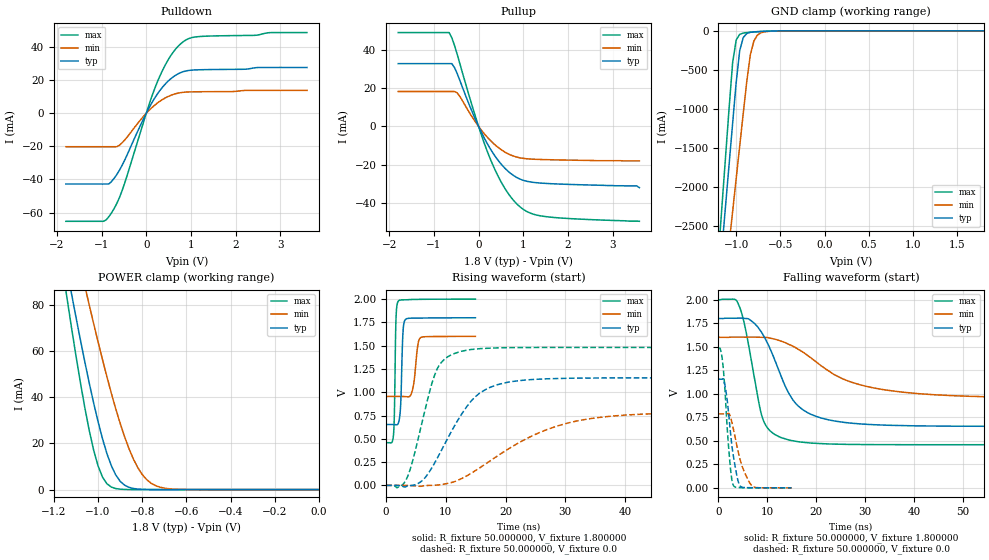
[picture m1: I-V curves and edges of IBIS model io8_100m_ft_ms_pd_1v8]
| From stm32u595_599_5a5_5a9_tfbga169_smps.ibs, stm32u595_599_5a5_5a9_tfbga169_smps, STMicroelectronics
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|   Model io8_100m_ft_ms_pd_1v8
[Model]  io8_100m_ft_ms_pd_1v8
Model_type I/O
Polarity   Non-Inverting
Enable   Active-Low
Vinl =   0.540000V
Vinh =   1.260000V
Vmeas =  0.900000V
Cref =   50.000000pF
Rref =   100.000000M
Vref =   0.0V
C_comp   3.148300pF   3.147400pF   3.196500pF
[Temperature Range]   25.000000   0.140000k   -40.000000
[Pullup Reference]   1.800000V   1.600000V   2.000000V
[Pulldown Reference]   0.0V   0.0V   0.0V
[POWER Clamp Reference]   1.800000V   1.600000V   2.000000V
[GND Clamp Reference]   0.0V   0.0V   0.0V
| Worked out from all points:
|   slope of the pulldown table from 0 to 0.27 V, typ, clamps not added: 21.7 ohm
|   slope of the pullup table from 0 to 0.27 V, typ, clamps not added: 22.6 ohm
|   GND clamp passes 1 mA (typ) near -0.51 V on its own axis
|   POWER clamp passes 1 mA (typ) near -0.86 V on its own axis
|   rising waveform, R_fixture 50.000000, V_fixture 1.800000: 20-80 % time 319ps typ, 632ps min, 231ps max; typ from 0.654 V to 1.8 V
|   rising waveform, R_fixture 50.000000, V_fixture 0.0: 20-80 % time 6.48ns typ, 13.4ns min, 3.56ns max; typ from 0 V to 1.15 V
|   falling waveform, R_fixture 50.000000, V_fixture 1.800000: 20-80 % time 6.37ns typ, 13.5ns min, 3.36ns max; typ from 1.8 V to 0.654 V
|   falling waveform, R_fixture 50.000000, V_fixture 0.0: 20-80 % time 1.6ns typ, 2.38ns min, 1.18ns max; typ from 1.15 V to 0 V
[Pulldown]
|Voltage   I(typ)   I(min)   I(max)
-1.8V     -42.74mA   -20.21mA   -65.25mA
-960mV    -42.74mA   -20.21mA   -65.25mA
-780mV    -41.3mA    -20.21mA   -60.25mA
-660mV    -37mA      -20.2mA    -54.5mA
-540mV    -31.39mA   -17.82mA   -46.65mA
0V        0A         100fA      0A
240mV     11.28mA    6.002mA    18.38mA
480mV     19.17mA    10.02mA    31.83mA
780mV     24.67mA    12.5mA     42.21mA
960mV     25.9mA     12.9mA     45.21mA
1.14V     26.24mA    12.99mA    46.23mA
3.6V      27.67mA    13.81mA    48.75mA
[Pullup]
|Voltage   I(typ)   I(min)   I(max)
-1.8V     32.87mA    18.3mA     49.13mA
-660mV    32.87mA    18.3mA     49.13mA
-600mV    32.87mA    18.3mA     46.41mA
-480mV    27.73mA    17.56mA    37.8mA
-60mV     3.108mA    1.975mA    4.436mA
240mV     -10.82mA   -6.752mA   -15.73mA
420mV     -17.18mA   -10.64mA   -25.23mA
600mV     -22.1mA    -13.54mA   -32.82mA
960mV     -27.82mA   -16.55mA   -42.66mA
1.2V      -29.16mA   -17.09mA   -45.68mA
1.56V     -29.85mA   -17.37mA   -47.3mA
3.6V      -32mA      -18mA      -49.6mA
[GND_clamp]
|Voltage   I(typ)   I(min)   I(max)
-1.8V     -9.707A    -9.942A    -9.774A
-1.2V     -3.309A    -4.006A    -2.865A
-1.16V    -2.777A    -3.584A    -2.239A
-1.12V    -2.246A    -3.162A    -1.614A
-1.04V    -1.186A    -2.319A    -408.7mA
-1V       -663.9mA   -1.898A    -117.8mA
-960mV    -254mA     -1.478A    -45.15mA
-920mV    -86.04mA   -1.06A     -28.6mA
-840mV    -19.13mA   -308.9mA   -18.75mA
-800mV    -13.4mA    -130.8mA   -15.33mA
-720mV    -7.959mA   -25.38mA   -9.395mA
1.8V      45.71uA    33.33uA    56.11uA
[POWER_clamp]
|Voltage   I(typ)   I(min)   I(max)
-1.8V     470.8mA    433.7mA    554.6mA
-1.14V    95.25mA    122.7mA    82.82mA
-1.12V    84.97mA    114mA      70.27mA
-1.06V    55.51mA    88.42mA    35.67mA
-1.04V    46.34mA    80.15mA    25.76mA
-1V       29.51mA    64.13mA    10.3mA
-940mV    10.39mA    41.86mA    1.109mA
-900mV    3.624mA    28.77mA    182.8uA
-840mV    490.7uA    13.24mA    11.35uA
-800mV    116.8uA    6.532mA    1.77uA
-740mV    13.2uA     1.723mA    109.3nA
0V        0A         18.72nA    0A
[Ramp]
| variable   typ   min   max
dV/dt_r  0.69264/6.46919n   0.47164/13.34441n   0.88830/3.56051n
dV/dt_f  0.68753/6.36026n   0.38683/13.47507n   0.92452/3.34799n
R_load = 50.000000
[Rising Waveform]
R_fixture= 50.000000
V_fixture= 1.800000
V_fixture_min= 1.600000
V_fixture_max= 2.000000
|time   V(typ)   V(min)   V(max)
0s        653.5mV    954.4mV    458.5mV
1.231ns   653.4mV    954.4mV    543.8mV
1.652ns   650.6mV    954.4mV    1.793V
2.012ns   663.5mV    954.5mV    1.976V
2.432ns   866.1mV    954.4mV    1.99V
2.853ns   1.674V     954.2mV    1.992V
3.213ns   1.78V      953.2mV    1.992V
4.414ns   1.795V     1.025V     1.995V
5.676ns   1.796V     1.581V     1.997V
14.95ns   1.799V     1.599V     1.999V
[Rising Waveform]
R_fixture= 50.000000
V_fixture= 0.0
V_fixture_min= 0.0
V_fixture_max= 0.0
|time   V(typ)   V(min)   V(max)
0s        3.631uV    3.094uV    2.535uV
3.203ns   -17.22mV   118.3uV    44.34mV
6.006ns   49.36mV    -7.78mV    673.8mV
8.408ns   273.4mV    2.738mV    1.231V
12.61ns   761.6mV    72.13mV    1.44V
15.62ns   988mV      185.6mV    1.467V
18.62ns   1.08V      314.6mV    1.476V
26.83ns   1.144V     596.4mV    1.48V
35.44ns   1.153V     727.3mV    1.48V
99.7ns    1.154V     786.2mV    1.48V
[Falling Waveform]
R_fixture= 50.000000
V_fixture= 1.800000
V_fixture_min= 1.600000
V_fixture_max= 2.000000
|time   V(typ)   V(min)   V(max)
0s        1.799V     1.599V     1.999V
3.804ns   1.803V     1.602V     1.981V
5.405ns   1.8V       1.601V     1.717V
8.408ns   1.683V     1.6V       866.4mV
9.209ns   1.618V     1.599V     713.7mV
14.41ns   1.003V     1.524V     508.5mV
17.22ns   832.1mV    1.445V     484.8mV
21.02ns   742.1mV    1.297V     470.3mV
34.63ns   665.4mV    1.037V     459.2mV
99.7ns    653.5mV    954.4mV    458.5mV
[Falling Waveform]
R_fixture= 50.000000
V_fixture= 0.0
V_fixture_min= 0.0
V_fixture_max= 0.0
|time   V(typ)   V(min)   V(max)
0s        1.154V     786.2mV    1.48V
750.8ps   1.155V     786.2mV    1.377V
1.321ns   1.091V     786.1mV    1.043V
1.802ns   922.7mV    787.6mV    621.8mV
2.312ns   662.1mV    774.6mV    283.9mV
2.703ns   467.2mV    705.1mV    97.18mV
3.093ns   323.6mV    614.9mV    22.17mV
4.444ns   18.73mV    296.3mV    2.615mV
6.787ns   1.414mV    24.79mV    615.3uV
14.95ns   3.631uV    3.094uV    2.535uV
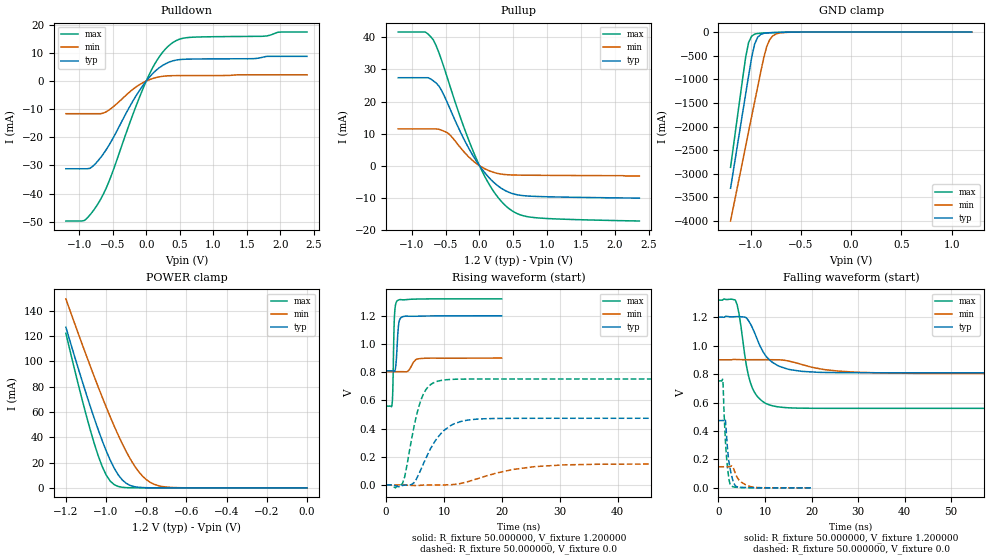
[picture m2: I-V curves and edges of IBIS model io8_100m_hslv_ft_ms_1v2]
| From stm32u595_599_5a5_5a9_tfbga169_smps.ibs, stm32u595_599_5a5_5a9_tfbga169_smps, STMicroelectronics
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|   Model io8_100m_hslv_ft_ms_1v2
[Model]  io8_100m_hslv_ft_ms_1v2
Model_type I/O
Polarity   Non-Inverting
Enable   Active-Low
Vinl =   0.360000V
Vinh =   0.840000V
Vmeas =  0.600000V
Cref =   50.000000pF
Rref =   100.000000M
Vref =   0.0V
C_comp   3.030100pF   2.960800pF   3.078300pF
[Temperature Range]   25.000000   0.140000k   -40.000000
[Pullup Reference]   1.200000V   0.900000V   1.320000V
[Pulldown Reference]   0.0V   0.0V   0.0V
[POWER Clamp Reference]   1.200000V   0.900000V   1.320000V
[GND Clamp Reference]   0.0V   0.0V   0.0V
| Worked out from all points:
|   slope of the pulldown table from 0 to 0.18 V, typ, clamps not added: 40.7 ohm
|   slope of the pullup table from 0 to 0.18 V, typ, clamps not added: 39.5 ohm
|   GND clamp passes 1 mA (typ) near -0.51 V on its own axis
|   POWER clamp passes 1 mA (typ) near -0.86 V on its own axis
|   rising waveform, R_fixture 50.000000, V_fixture 1.200000: 20-80 % time 356ps typ, 869ps min, 231ps max; typ from 0.809 V to 1.2 V
|   rising waveform, R_fixture 50.000000, V_fixture 0.0: 20-80 % time 3.94ns typ, 8.94ns min, 2.36ns max; typ from 0 V to 0.473 V
|   falling waveform, R_fixture 50.000000, V_fixture 1.200000: 20-80 % time 4.07ns typ, 8.67ns min, 2.49ns max; typ from 1.2 V to 0.809 V
|   falling waveform, R_fixture 50.000000, V_fixture 0.0: 20-80 % time 1.04ns typ, 1.97ns min, 798ps max; typ from 0.473 V to 0 V
[Pulldown]
|Voltage   I(typ)   I(min)   I(max)
-1.2V     -31.16mA   -11.61mA   -49.71mA
-920mV    -31.16mA   -11.61mA   -49.48mA
-840mV    -31mA      -11.61mA   -47.54mA
-720mV    -28.32mA   -11.61mA   -43.58mA
-560mV    -22.95mA   -10.37mA   -35.89mA
-200mV    -7.146mA   -2.964mA   -11.89mA
0V        0A         -900fA     0A
160mV     4.047mA    1.298mA    7.361mA
360mV     6.87mA     1.87mA     13mA
640mV     7.764mA    1.923mA    15.46mA
1.76V     8.564mA    2.187mA    15.9mA
2.4V      8.742mA    2.187mA    17.38mA
[Pullup]
|Voltage   I(typ)   I(min)   I(max)
-1.2V     27.43mA    11.47mA    41.67mA
-800mV    27.43mA    11.47mA    41.67mA
-680mV    26.42mA    11.47mA    39.17mA
-600mV    24.87mA    11.36mA    35.26mA
-440mV    17.97mA    9.699mA    25.09mA
-240mV    8.719mA    4.584mA    12.56mA
-40mV     1.247mA    576.2uA    1.879mA
200mV     -4.978mA   -2.01mA    -7.739mA
440mV     -8.335mA   -2.843mA   -13.44mA
600mV     -9.206mA   -2.931mA   -15.29mA
840mV     -9.571mA   -2.98mA    -16.23mA
2.36V     -10.1mA    -3.2mA     -17.23mA
[GND_clamp]
|Voltage   I(typ)   I(min)   I(max)
-1.2V     -3.305A    -3.998A    -2.862A
-1.05V    -1.316A    -2.418A    -539.3mA
-1.02V    -921mA     -2.103A    -218.8mA
-990mV    -539.5mA   -1.788A    -87.43mA
-960mV    -252.1mA   -1.474A    -44.36mA
-930mV    -110.5mA   -1.16A     -30.32mA
-870mV    -28.03mA   -549.1mA   -21.09mA
-840mV    -18.43mA   -305.6mA   -18.27mA
-810mV    -13.9mA    -159.7mA   -15.73mA
-780mV    -11.23mA   -82.35mA   -13.37mA
-600mV    -2.976mA   -4.272mA   -3.058mA
1.2V      0A         14.73nA    0A
[POWER_clamp]
|Voltage   I(typ)   I(min)   I(max)
-1.2V     127mA      149.4mA    122.2mA
-1.12V    84.97mA    114mA      70.27mA
-1.06V    55.51mA    88.42mA    35.67mA
-1.02V    37.63mA    72.04mA    17.17mA
-1V       29.51mA    64.13mA    10.3mA
-960mV    15.69mA    48.99mA    2.571mA
-900mV    3.624mA    28.77mA    182.8uA
-840mV    490.7uA    13.24mA    11.35uA
-800mV    116.8uA    6.532mA    1.77uA
-740mV    13.2uA     1.723mA    109.1nA
-620mV    167.3nA    79.35uA    0A
0V        0A         17.84nA    0A
[Ramp]
| variable   typ   min   max
dV/dt_r  0.28375/3.90597n   88.91987m/8.93167n  0.45093/2.35229n
dV/dt_f  0.23463/4.02925n   57.91200m/8.66486n  0.45666/2.47766n
R_load = 50.000000
[Rising Waveform]
R_fixture= 50.000000
V_fixture= 1.200000
V_fixture_min= 0.900000
V_fixture_max= 1.320000
|time   V(typ)   V(min)   V(max)
0s        809mV      803.5mV    558.9mV
1.041ns   809.4mV    803.5mV    578.2mV
1.161ns   809.1mV    803.5mV    693.9mV
1.321ns   806.9mV    803.6mV    1.049V
1.441ns   805.2mV    803.6mV    1.204V
1.922ns   1.007V     803.6mV    1.307V
2.242ns   1.16V      803.7mV    1.314V
2.923ns   1.194V     803.4mV    1.313V
5.726ns   1.197V     895.5mV    1.319V
19.94ns   1.2V       900mV      1.32V
[Rising Waveform]
R_fixture= 50.000000
V_fixture= 0.0
V_fixture_min= 0.0
V_fixture_max= 0.0
|time   V(typ)   V(min)   V(max)
0s        2.231nV    213nV      1.42nV
2.803ns   -4.399mV   53.9uV     8.088mV
3.203ns   -1.385mV   38.83uV    57.98mV
4.805ns   15.36mV    -4.229mV   412.6mV
6.406ns   147.7mV    -1.253mV   642.3mV
8.008ns   280.7mV    -164.1uV   720.8mV
10.41ns   399.2mV    308.8uV    746.4mV
15.22ns   465.1mV    36.85mV    751.2mV
30.83ns   472.8mV    142.1mV    751.5mV
199.4ns   472.9mV    148.2mV    751.6mV
[Falling Waveform]
R_fixture= 50.000000
V_fixture= 1.200000
V_fixture_min= 0.900000
V_fixture_max= 1.320000
|time   V(typ)   V(min)   V(max)
0s        1.2V       900mV      1.32V
3.604ns   1.203V     902.5mV    1.321V
4.004ns   1.204V     901.9mV    1.288V
6.006ns   1.196V     900.8mV    858.6mV
7.608ns   1.102V     900.9mV    679.2mV
10.01ns   934.9mV    900.9mV    596.2mV
13.21ns   852.7mV    900.1mV    567.7mV
22.82ns   811.3mV    831.1mV    559.1mV
35.24ns   809mV      807.5mV    558.9mV
199.4ns   809mV      803.5mV    558.9mV
[Falling Waveform]
R_fixture= 50.000000
V_fixture= 0.0
V_fixture_min= 0.0
V_fixture_max= 0.0
|time   V(typ)   V(min)   V(max)
0s        472.9mV    148.2mV    751.6mV
920.9ps   473.2mV    148.3mV    760.5mV
1.201ns   474.7mV    148.3mV    524.5mV
1.441ns   482.1mV    148.4mV    360.6mV
1.682ns   391.2mV    148.4mV    236.8mV
2.202ns   194.6mV    148.2mV    72.35mV
2.683ns   104.6mV    152.2mV    16.41mV
3.764ns   10.77mV    90.01mV    3.994mV
6.767ns   1.663mV    9.962mV    590uV
19.94ns   2.231nV    213nV      1.42nV
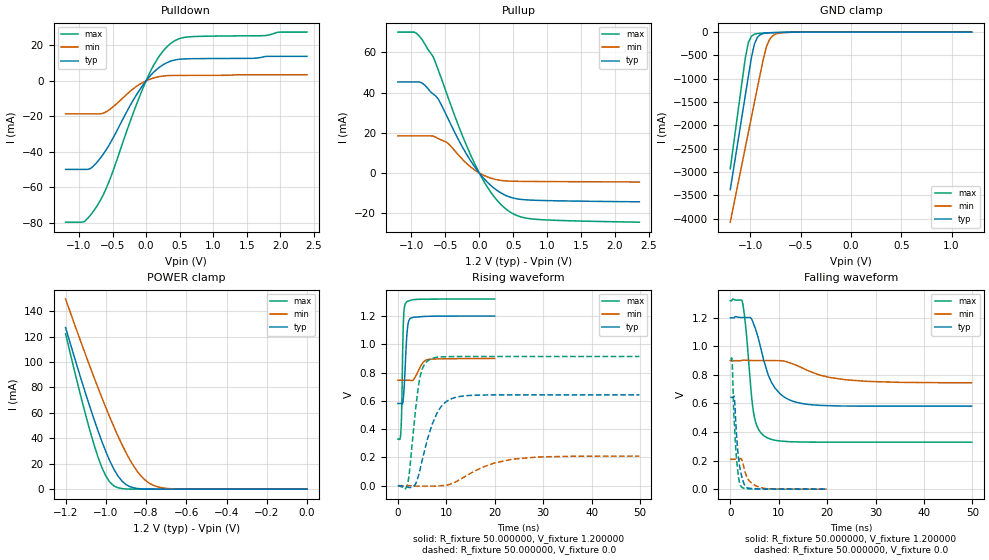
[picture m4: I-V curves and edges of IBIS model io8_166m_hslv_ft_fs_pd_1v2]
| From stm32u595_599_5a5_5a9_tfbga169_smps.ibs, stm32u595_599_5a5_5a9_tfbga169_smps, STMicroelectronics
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|   Model io8_166m_hslv_ft_fs_pd_1v2
[Model]  io8_166m_hslv_ft_fs_pd_1v2
Model_type I/O
Polarity   Non-Inverting
Enable   Active-Low
Vinl =   0.360000V
Vinh =   0.840000V
Vmeas =  0.600000V
Cref =   50.000000pF
Rref =   100.000000M
Vref =   0.0V
C_comp   3.151700pF   3.087200pF   3.197900pF
[Temperature Range]   25.000000   0.140000k   -40.000000
[Pullup Reference]   1.200000V   0.900000V   1.320000V
[Pulldown Reference]   0.0V   0.0V   0.0V
[POWER Clamp Reference]   1.200000V   0.900000V   1.320000V
[GND Clamp Reference]   0.0V   0.0V   0.0V
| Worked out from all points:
|   slope of the pulldown table from 0 to 0.18 V, typ, clamps not added: 25.4 ohm
|   slope of the pullup table from 0 to 0.18 V, typ, clamps not added: 27.8 ohm
|   GND clamp passes 1 mA (typ) near -0.51 V on its own axis
|   POWER clamp passes 1 mA (typ) near -0.86 V on its own axis
|   rising waveform, R_fixture 50.000000, V_fixture 1.200000: 20-80 % time 570ps typ, 1.42ns min, 326ps max; typ from 0.581 V to 1.2 V
|   rising waveform, R_fixture 50.000000, V_fixture 0.0: 20-80 % time 3.42ns typ, 8.15ns min, 1.74ns max; typ from 0 V to 0.642 V
|   falling waveform, R_fixture 50.000000, V_fixture 1.200000: 20-80 % time 3.69ns typ, 8.16ns min, 1.62ns max; typ from 1.2 V to 0.581 V
|   falling waveform, R_fixture 50.000000, V_fixture 0.0: 20-80 % time 1.04ns typ, 1.73ns min, 831ps max; typ from 0.642 V to 0 V
[Pulldown]
|Voltage   I(typ)   I(min)   I(max)
-1.2V     -49.86mA   -18.57mA   -79.56mA
-920mV    -49.86mA   -18.57mA   -79.19mA
-840mV    -49.6mA    -18.57mA   -76.08mA
-720mV    -45.32mA   -18.57mA   -69.74mA
-560mV    -36.71mA   -16.58mA   -57.44mA
-200mV    -11.43mA   -4.74mA    -19.03mA
0V        -10fA      -600fA     0A
160mV     6.477mA    2.075mA    11.78mA
360mV     10.99mA    2.99mA     20.81mA
480mV     12.07mA    3.054mA    23.53mA
640mV     12.43mA    3.075mA    24.76mA
2.4V      13.79mA    3.434mA    27.44mA
[Pullup]
|Voltage   I(typ)   I(min)   I(max)
-1.2V     45.31mA    18.46mA    70.12mA
-920mV    45.31mA    18.46mA    69.36mA
-840mV    44.69mA    18.46mA    66.16mA
-680mV    39.3mA     18.37mA    57.86mA
-600mV    36.53mA    16.99mA    50.82mA
-480mV    28.42mA    15.27mA    39.5mA
-280mV    14.84mA    7.943mA    21.22mA
-80mV     3.667mA    1.75mA     5.47mA
160mV     -5.889mA   -2.43mA    -9.115mA
400mV     -11.31mA   -3.958mA   -18.11mA
800mV     -13.54mA   -4.214mA   -22.92mA
2.36V     -14.3mA    -4.5mA     -24.47mA
[GND_clamp]
|Voltage   I(typ)   I(min)   I(max)
-1.2V     -3.379A    -4.076A    -2.932A
-1.05V    -1.35A     -2.47A     -550.7mA
-1.02V    -947.8mA   -2.15A     -221.5mA
-990mV    -552.4mA   -1.829A    -88.45mA
-960mV    -255.3mA   -1.51A     -44.89mA
-930mV    -111.8mA   -1.191A    -30.7mA
-870mV    -28.37mA   -564.6mA   -21.36mA
-840mV    -18.66mA   -309.5mA   -18.51mA
-810mV    -14.08mA   -161.6mA   -15.94mA
-780mV    -11.38mA   -83.33mA   -13.55mA
-600mV    -3.02mA    -4.329mA   -3.104mA
1.2V      30.28uA    18.17uA    37.27uA
[POWER_clamp]
|Voltage   I(typ)   I(min)   I(max)
-1.2V     127mA      149.4mA    122.2mA
-1.12V    84.97mA    114mA      70.27mA
-1.06V    55.51mA    88.42mA    35.67mA
-1.02V    37.63mA    72.04mA    17.17mA
-1V       29.51mA    64.13mA    10.3mA
-960mV    15.69mA    48.99mA    2.571mA
-900mV    3.624mA    28.77mA    182.8uA
-840mV    490.7uA    13.24mA    11.35uA
-800mV    116.8uA    6.532mA    1.77uA
-740mV    13.2uA     1.723mA    109.1nA
-620mV    167.4nA    79.36uA    0A
0V        0A         17.87nA    0A
[Ramp]
| variable   typ   min   max
dV/dt_r  0.38524/3.41600n   0.12534/8.13853n   0.54787/1.73624n
dV/dt_f  0.37096/3.68416n   92.53200m/8.16964n  0.59419/1.62055n
R_load = 50.000000
[Rising Waveform]
R_fixture= 50.000000
V_fixture= 1.200000
V_fixture_min= 0.900000
V_fixture_max= 1.320000
|time   V(typ)   V(min)   V(max)
0s        581.3mV    745.1mV    329.3mV
640.6ps   581.2mV    745.1mV    401.8mV
800.8ps   578.7mV    745.1mV    575.7mV
1.121ns   619mV      745.1mV    1.149V
1.321ns   717.3mV    745.1mV    1.256V
1.682ns   973.1mV    745.2mV    1.295V
2.122ns   1.149V     745.3mV    1.305V
2.843ns   1.187V     743.5mV    1.313V
6.206ns   1.198V     892.5mV    1.319V
19.94ns   1.2V       899.5mV    1.319V
[Rising Waveform]
R_fixture= 50.000000
V_fixture= 0.0
V_fixture_min= 0.0
V_fixture_max= 0.0
|time   V(typ)   V(min)   V(max)
0s        -5.805uV   233.2nV    -33.15uV
2.002ns   -9.168mV   -3.342uV   12mV
3.504ns   5.656mV    -2.806mV   492.1mV
4.404ns   92.41mV    -2.955mV   739.4mV
5.205ns   207.6mV    -2.962mV   839.5mV
6.406ns   362.4mV    -3.286mV   889.4mV
8.909ns   558mV      -278.1uV   910.5mV
12.51ns   629.1mV    37.93mV    913mV
23.52ns   642.1mV    186.8mV    913.3mV
49.85ns   642.2mV    209.1mV    913.3mV
[Falling Waveform]
R_fixture= 50.000000
V_fixture= 1.200000
V_fixture_min= 0.900000
V_fixture_max= 1.320000
|time   V(typ)   V(min)   V(max)
0s        1.2V       899.5mV    1.319V
2.503ns   1.202V     902.6mV    1.313V
3.203ns   1.202V     902.6mV    1.133V
4.805ns   1.159V     900.4mV    537.9mV
5.706ns   1.067V     900.2mV    427.7mV
7.307ns   857.9mV    900.1mV    366mV
10.31ns   666.8mV    899.6mV    337.2mV
15.02ns   598.4mV    846.2mV    329.9mV
23.92ns   582.2mV    765.5mV    329.3mV
49.85ns   581.3mV    745.1mV    329.3mV
[Falling Waveform]
R_fixture= 50.000000
V_fixture= 0.0
V_fixture_min= 0.0
V_fixture_max= 0.0
|time   V(typ)   V(min)   V(max)
0s        642.2mV    209.1mV    913.3mV
400.4ps   642.2mV    209.1mV    886.3mV
680.7ps   647.3mV    209.2mV    573mV
840.8ps   643.4mV    209.2mV    462mV
1.441ns   314mV      209.1mV    161.6mV
1.842ns   182.5mV    210.2mV    57.52mV
2.202ns   113.2mV    214.1mV    19.84mV
3.243ns   15mV       101.4mV    3.353mV
5.806ns   1.787mV    16.01mV    457.8uV
19.94ns   -5.805uV   233.2nV    -33.15uV
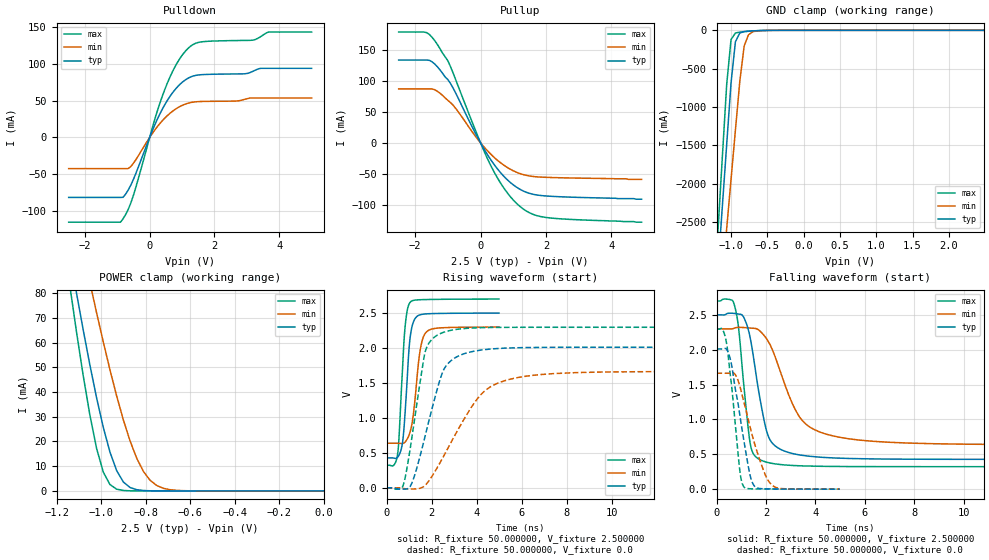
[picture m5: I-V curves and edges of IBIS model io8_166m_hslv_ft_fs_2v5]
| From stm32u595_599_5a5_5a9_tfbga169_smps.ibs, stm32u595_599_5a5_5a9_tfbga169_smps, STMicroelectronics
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|   Model io8_166m_hslv_ft_fs_2v5
[Model]  io8_166m_hslv_ft_fs_2v5
Model_type I/O
Polarity   Non-Inverting
Enable   Active-Low
Vinl =   0.750000V
Vinh =   1.750000V
Vmeas =  1.250000V
Cref =   50.000000pF
Rref =   100.000000M
Vref =   0.0V
C_comp   3.458600pF   3.458000pF   3.495600pF
[Temperature Range]   25.000000   0.140000k   -40.000000
[Pullup Reference]   2.500000V   2.300000V   2.700000V
[Pulldown Reference]   0.0V   0.0V   0.0V
[POWER Clamp Reference]   2.500000V   2.300000V   2.700000V
[GND Clamp Reference]   0.0V   0.0V   0.0V
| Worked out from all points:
|   slope of the pulldown table from 0 to 0.375 V, typ, clamps not added: 10.1 ohm
|   slope of the pullup table from 0 to 0.375 V, typ, clamps not added: 11.7 ohm
|   GND clamp passes 1 mA (typ) near -0.50 V on its own axis
|   POWER clamp passes 1 mA (typ) near -0.86 V on its own axis
|   rising waveform, R_fixture 50.000000, V_fixture 2.500000: 20-80 % time 255ps typ, 337ps min, 236ps max; typ from 0.428 V to 2.5 V
|   rising waveform, R_fixture 50.000000, V_fixture 0.0: 20-80 % time 990ps typ, 1.85ns min, 648ps max; typ from 0 V to 2.01 V
|   falling waveform, R_fixture 50.000000, V_fixture 2.500000: 20-80 % time 613ps typ, 1.21ns min, 386ps max; typ from 2.5 V to 0.428 V
|   falling waveform, R_fixture 50.000000, V_fixture 0.0: 20-80 % time 562ps typ, 786ps min, 389ps max; typ from 2.01 V to 0 V
[Pulldown]
|Voltage   I(typ)   I(min)   I(max)
-2.5V     -81.62mA   -42.31mA   -115.3mA
-900mV    -81.62mA   -42.31mA   -115.3mA
-820mV    -81.43mA   -42.31mA   -110.6mA
-500mV    -56.95mA   -35.08mA   -78.57mA
140mV     15.18mA    9.02mA     22.02mA
460mV     44mA       25.98mA    64.38mA
860mV     68.91mA    40.27mA    102.2mA
1.26V     82.21mA    47.42mA    124mA
1.66V     85.54mA    49mA       130.3mA
3.18V     89.84mA    53.64mA    132.3mA
3.66V     94.01mA    53.64mA    143.3mA
5V        94.01mA    53.64mA    143.3mA
[Pullup]
|Voltage   I(typ)   I(min)   I(max)
-2.5V     133.3mA    86.84mA    178.4mA
-1.64V    133.3mA    86.84mA    177.4mA
-1.4V     127mA      85.43mA    164.7mA
-1V       102mA      68.42mA    132.3mA
-920mV    95.91mA    64.95mA    123.1mA
-120mV    11.81mA    8.046mA    15.6mA
360mV     -30.97mA   -20.78mA   -41.56mA
760mV     -56.64mA   -37.85mA   -76.55mA
1.24V     -75.99mA   -50.28mA   -104.1mA
1.64V     -83.42mA   -54.54mA   -116.1mA
2.04V     -85.88mA   -55.77mA   -120.6mA
4.92V     -91mA      -59mA      -128mA
[GND_clamp]
|Voltage   I(typ)   I(min)   I(max)
-2.5V     -9.641A    -9.693A    -9.352A
-1.18V    -3.114A    -3.874A    -2.614A
-1.12V    -2.301A    -3.23A     -1.656A
-1.06V    -1.489A    -2.587A    -706.2mA
-1V       -685.8mA   -1.945A    -119.3mA
-940mV    -149.7mA   -1.304A    -34.73mA
-880mV    -35.54mA   -672.6mA   -23.06mA
-820mV    -16.2mA    -206.4mA   -17.27mA
-760mV    -10.58mA   -57.55mA   -12.41mA
-700mV    -7.152mA   -18.74mA   -8.24mA
-400mV    -103.3uA   -378.6uA   -41.75uA
2.48V     0A         13.22nA    0A
[POWER_clamp]
|Voltage   I(typ)   I(min)   I(max)
-2.49V    881mA      773.1mA    1.07A
-1.14V    95.25mA    122.7mA    82.82mA
-1.11V    79.9mA     109.7mA    64.14mA
-1.05V    50.87mA    84.26mA    30.57mA
-1.02V    37.63mA    72.04mA    17.17mA
-990mV    25.71mA    60.25mA    7.621mA
-930mV    8.217mA    38.43mA    713.9uA
-900mV    3.624mA    28.77mA    182.8uA
-840mV    490.7uA    13.24mA    11.35uA
-780mV    56.55uA    4.324mA    699nA
-660mV    716.7nA    226uA      9.784nA
0V        0A         19.53nA    0A
[Ramp]
| variable   typ   min   max
dV/dt_r  1.20666/0.98843n   0.99780/1.84731n   1.37784/0.64673n
dV/dt_f  1.24345/0.61154n   0.99745/1.21079n   1.42637/0.38518n
R_load = 50.000000
[Rising Waveform]
R_fixture= 50.000000
V_fixture= 2.500000
V_fixture_min= 2.300000
V_fixture_max= 2.700000
|time   V(typ)   V(min)   V(max)
0s        427.5mV    637.5mV    322.7mV
490.5ps   437.2mV    637.6mV    479.5mV
550.6ps   466mV      637.1mV    704.4mV
680.7ps   592.6mV    633.3mV    1.533V
800.8ps   968.8mV    647.6mV    2.218V
1.031ns   2.102V     784.9mV    2.646V
1.201ns   2.379V     1.081V     2.681V
1.491ns   2.475V     1.967V     2.69V
1.722ns   2.487V     2.211V     2.693V
4.985ns   2.5V       2.3V       2.7V
[Rising Waveform]
R_fixture= 50.000000
V_fixture= 0.0
V_fixture_min= 0.0
V_fixture_max= 0.0
|time   V(typ)   V(min)   V(max)
0s        -33.59uV   -11.68uV   -38.56uV
720.7ps   -19.35mV   -7.041mV   20.91mV
1.081ns   37.97mV    -17.08mV   626.5mV
1.722ns   753.3mV    38.24mV    1.953V
2.002ns   1.113V     157.1mV    2.12V
2.482ns   1.65V      423mV      2.219V
3.043ns   1.86V      758mV      2.263V
4.164ns   1.969V     1.326V     2.29V
5.686ns   2.002V     1.568V     2.296V
19.94ns   2.011V     1.663V     2.296V
[Falling Waveform]
R_fixture= 50.000000
V_fixture= 2.500000
V_fixture_min= 2.300000
V_fixture_max= 2.700000
|time   V(typ)   V(min)   V(max)
0s        2.5V       2.3V       2.7V
720.7ps   2.521V     2.31V      2.644V
880.9ps   2.513V     2.321V     2.35V
1.121ns   2.451V     2.318V     1.428V
1.401ns   2.098V     2.31V      588.9mV
1.922ns   992.6mV    2.206V     398.7mV
2.282ns   650.3mV    1.981V     367.6mV
3.363ns   491.1mV    1.034V     335.6mV
4.685ns   448.9mV    766.1mV    326.2mV
19.94ns   427.5mV    637.5mV    322.7mV
[Falling Waveform]
R_fixture= 50.000000
V_fixture= 0.0
V_fixture_min= 0.0
V_fixture_max= 0.0
|time   V(typ)   V(min)   V(max)
0s        2.011V     1.663V     2.296V
230.2ps   2.011V     1.663V     2.297V
400.4ps   2.01V      1.663V     2.107V
600.6ps   1.797V     1.666V     1.511V
940.9ps   1.067V     1.479V     270.2mV
1.111ns   686.3mV    1.244V     31.61mV
1.481ns   71.39mV    725mV      4.355mV
1.922ns   5.547mV    249.6mV    2.167mV
2.222ns   3.169mV    65.7mV     1.622mV
4.985ns   -33.59uV   -11.68uV   -38.56uV
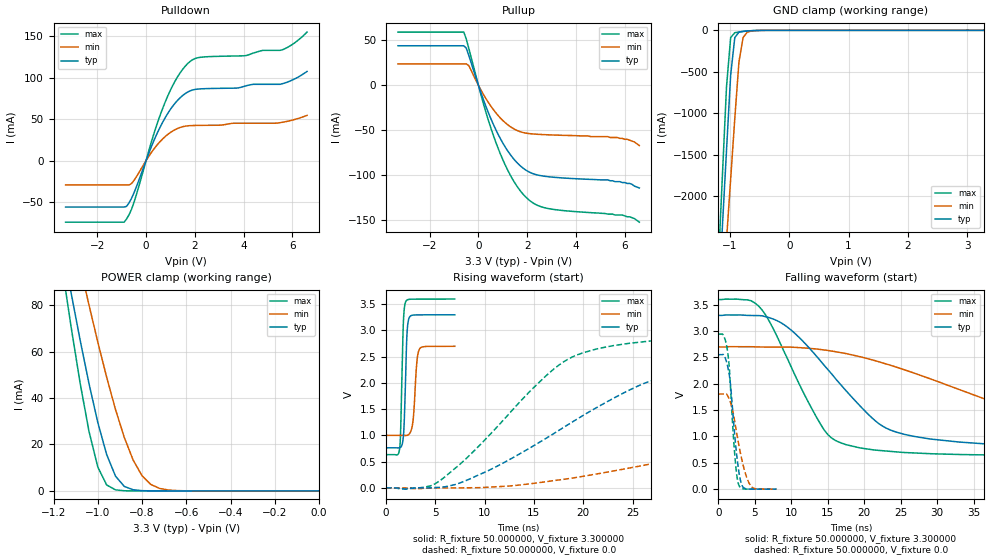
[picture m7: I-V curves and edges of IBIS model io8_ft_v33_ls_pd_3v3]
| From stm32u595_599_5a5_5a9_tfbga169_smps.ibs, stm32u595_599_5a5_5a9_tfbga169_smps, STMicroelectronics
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|   Model io8_ft_v33_ls_pd_3v3
[Model]  io8_ft_v33_ls_pd_3v3
Model_type I/O
Polarity   Non-Inverting
Enable   Active-Low
Vinl =   0.990000V
Vinh =   2.310000V
Vmeas =  1.650000V
Cref =   50.000000pF
Rref =   100.000000M
Vref =   0.0V
C_comp   3.252200pF   3.221000pF   3.293600pF
[Temperature Range]   25.000000   0.140000k   -40.000000
[Pullup Reference]   3.300000V   2.700000V   3.600000V
[Pulldown Reference]   0.0V   0.0V   0.0V
[POWER Clamp Reference]   3.300000V   2.700000V   3.600000V
[GND Clamp Reference]   0.0V   0.0V   0.0V
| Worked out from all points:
|   slope of the pulldown table from 0 to 0.495 V, typ, clamps not added: 14 ohm
|   slope of the pullup table from 0 to 0.495 V, typ, clamps not added: 13.7 ohm
|   GND clamp passes 1 mA (typ) near -0.50 V on its own axis
|   POWER clamp passes 1 mA (typ) near -0.85 V on its own axis
|   rising waveform, R_fixture 50.000000, V_fixture 3.300000: 20-80 % time 245ps typ, 337ps min, 229ps max; typ from 0.764 V to 3.3 V
|   rising waveform, R_fixture 50.000000, V_fixture 0.0: 20-80 % time 14.7ns typ, 31.2ns min, 9.34ns max; typ from 0 V to 2.55 V
|   falling waveform, R_fixture 50.000000, V_fixture 3.300000: 20-80 % time 10ns typ, 23.1ns min, 6.37ns max; typ from 3.3 V to 0.764 V
|   falling waveform, R_fixture 50.000000, V_fixture 0.0: 20-80 % time 1.01ns typ, 1.54ns min, 814ps max; typ from 2.55 V to 0 V
[Pulldown]
|Voltage   I(typ)   I(min)   I(max)
-3.3V     -56.06mA   -29.42mA   -74.35mA
-900mV    -56.06mA   -29.42mA   -74.35mA
-700mV    -51.09mA   -29.42mA   -65.48mA
-500mV    -39.32mA   -24.2mA    -50.88mA
300mV     22.62mA    13.13mA    30.42mA
800mV     52.54mA    29.36mA    71.75mA
1.3V      72.91mA    38.82mA    101.4mA
1.8V      84.02mA    42.13mA    119.4mA
2.2V      86.43mA    42.46mA    124.5mA
5.5V      92.01mA    45.75mA    133mA
6.1V      98.6mA     49.6mA     142.1mA
6.6V      107.5mA    54.5mA     155mA
[Pullup]
|Voltage   I(typ)   I(min)   I(max)
-3.3V     43.81mA    23.73mA    58.97mA
-600mV    43.81mA    23.73mA    58.97mA
-500mV    41.28mA    23.73mA    51.53mA
-400mV    33.57mA    21.9mA     41.51mA
300mV     -22.93mA   -14.5mA    -29.27mA
800mV     -54.04mA   -33.36mA   -69.41mA
1.4V      -80.24mA   -47.59mA   -104.2mA
2.1V      -96.56mA   -53.73mA   -127.9mA
3V        -101.9mA   -55.18mA   -137.5mA
5.7V      -107mA     -58mA      -144mA
6.2V      -109mA     -61mA      -146mA
6.6V      -114mA     -67mA      -152mA
[GND_clamp]
|Voltage   I(typ)   I(min)   I(max)
-3.3V     -9.848A    -9.957A    -9.458A
-1.2V     -3.312A    -4.013A    -2.863A
-1.13V    -2.381A    -3.274A    -1.769A
-1.06V    -1.452A    -2.535A    -684.8mA
-990mV    -542.9mA   -1.798A    -88.04mA
-920mV    -87.13mA   -1.064A    -28.45mA
-850mV    -22.11mA   -382.4mA   -19.62mA
-780mV    -11.98mA   -86.98mA   -13.73mA
-710mV    -7.63mA    -22.27mA   -8.759mA
-640mV    -4.504mA   -7.781mA   -4.831mA
-360mV    -39.8uA    -178.9uA   -19.56uA
3.28V     83.52uA    56.87uA    102.4uA
[POWER_clamp]
|Voltage   I(typ)   I(min)   I(max)
-3.28V    1.355A     1.167A     1.664A
-1.16V    105.7mA    131.6mA    95.69mA
-1.12V    84.97mA    114mA      70.27mA
-1.08V    65.05mA    96.83mA    46.54mA
-1.04V    46.34mA    80.15mA    25.76mA
-1V       29.51mA    64.13mA    10.3mA
-960mV    15.69mA    48.99mA    2.571mA
-920mV    6.373mA    35.1mA     455.6uA
-840mV    490.7uA    13.24mA    11.36uA
-760mV    27.33uA    2.767mA    276.6nA
-640mV    346.6nA    134.1uA    15.48nA
0V        0A         19.91nA    0A
[Ramp]
| variable   typ   min   max
dV/dt_r  1.53198/14.64160n   1.08384/31.21486n   1.76610/9.33319n
dV/dt_f  1.52116/10.02024n   1.01868/23.08794n   1.77921/6.36312n
R_load = 50.000000
[Rising Waveform]
R_fixture= 50.000000
V_fixture= 3.300000
V_fixture_min= 2.700000
V_fixture_max= 3.600000
|time   V(typ)   V(min)   V(max)
0s        763.9mV    1.001V     633.7mV
1.387ns   763.5mV    1.001V     737mV
1.499ns   775.1mV    1.001V     1.107V
1.766ns   961.5mV    1.001V     3.113V
2.004ns   2.112V     999.1mV    3.545V
2.13ns    2.895V     1.001V     3.578V
2.298ns   3.205V     1.014V     3.591V
2.747ns   3.293V     1.269V     3.597V
3.363ns   3.298V     2.63V      3.598V
6.979ns   3.299V     2.699V     3.599V
[Rising Waveform]
R_fixture= 50.000000
V_fixture= 0.0
V_fixture_min= 0.0
V_fixture_max= 0.0
|time   V(typ)   V(min)   V(max)
0s        16.97nV    116.6nV    53.79nV
5.506ns   12.1mV     -417.1uV   140.6mV
10.51ns   341.1mV    15.04mV    1.01V
18.52ns   1.213V     176.8mV    2.46V
25.53ns   1.94V      409.1mV    2.773V
29.53ns   2.181V     556.6mV    2.841V
40.54ns   2.422V     976.7mV    2.913V
55.56ns   2.512V     1.449V     2.937V
77.08ns   2.545V     1.689V     2.943V
249.2ns   2.553V     1.806V     2.943V
[Falling Waveform]
R_fixture= 50.000000
V_fixture= 3.300000
V_fixture_min= 2.700000
V_fixture_max= 3.600000
|time   V(typ)   V(min)   V(max)
0s        3.299V     2.699V     3.599V
5.005ns   3.296V     2.702V     3.537V
6.507ns   3.274V     2.698V     3.305V
9.009ns   3.124V     2.697V     2.617V
15.02ns   2.273V     2.634V     1.037V
21.52ns   1.298V     2.439V     741.7mV
29.03ns   952.7mV    2.096V     673.7mV
43.54ns   819.6mV    1.416V     641.5mV
62.56ns   779.2mV    1.149V     635mV
249.2ns   763.9mV    1.001V     633.7mV
[Falling Waveform]
R_fixture= 50.000000
V_fixture= 0.0
V_fixture_min= 0.0
V_fixture_max= 0.0
|time   V(typ)   V(min)   V(max)
0s        2.553V     1.806V     2.943V
720.7ps   2.554V     1.806V     2.916V
1.281ns   2.342V     1.777V     2.622V
1.65ns    2.033V     1.661V     2.024V
2.306ns   963.8mV    1.252V     593.1mV
2.595ns   581.1mV    1.019V     219.2mV
2.819ns   343.3mV    846.3mV    79.79mV
3.347ns   48.44mV    495.3mV    8.776mV
4.549ns   810.5uV    47.39mV    590uV
7.976ns   16.97nV    116.6nV    53.79nV
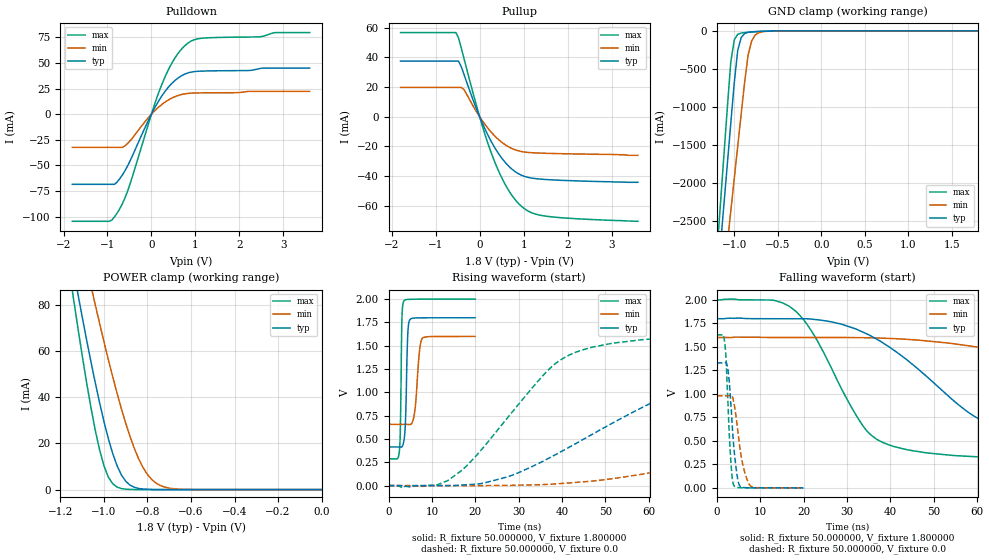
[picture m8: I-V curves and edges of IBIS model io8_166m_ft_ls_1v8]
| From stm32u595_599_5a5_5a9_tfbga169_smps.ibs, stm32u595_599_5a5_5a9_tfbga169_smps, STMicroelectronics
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|   Model io8_166m_ft_ls_1v8
[Model]  io8_166m_ft_ls_1v8
Model_type I/O
Polarity   Non-Inverting
Enable   Active-Low
Vinl =   0.540000V
Vinh =   1.260000V
Vmeas =  0.900000V
Cref =   50.000000pF
Rref =   100.000000M
Vref =   0.0V
C_comp   3.358100pF   3.352600pF   3.400200pF
[Temperature Range]   25.000000   0.140000k   -40.000000
[Pullup Reference]   1.800000V   1.600000V   2.000000V
[Pulldown Reference]   0.0V   0.0V   0.0V
[POWER Clamp Reference]   1.800000V   1.600000V   2.000000V
[GND Clamp Reference]   0.0V   0.0V   0.0V
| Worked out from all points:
|   slope of the pulldown table from 0 to 0.27 V, typ, clamps not added: 13.6 ohm
|   slope of the pullup table from 0 to 0.27 V, typ, clamps not added: 15.9 ohm
|   GND clamp passes 1 mA (typ) near -0.51 V on its own axis
|   POWER clamp passes 1 mA (typ) near -0.86 V on its own axis
|   rising waveform, R_fixture 50.000000, V_fixture 1.800000: 20-80 % time 443ps typ, 900ps min, 293ps max; typ from 0.414 V to 1.8 V
|   rising waveform, R_fixture 50.000000, V_fixture 0.0: 20-80 % time 33.9ns typ, 74.7ns min, 18ns max; typ from 0 V to 1.33 V
|   falling waveform, R_fixture 50.000000, V_fixture 1.800000: 20-80 % time 23.4ns typ, 59.1ns min, 12.2ns max; typ from 1.8 V to 0.414 V
|   falling waveform, R_fixture 50.000000, V_fixture 0.0: 20-80 % time 1.32ns typ, 1.9ns min, 975ps max; typ from 1.33 V to 0 V
[Pulldown]
|Voltage   I(typ)   I(min)   I(max)
-1.8V     -68.38mA   -32.32mA   -104.4mA
-960mV    -68.38mA   -32.32mA   -104.4mA
-780mV    -66.08mA   -32.32mA   -96.42mA
-660mV    -59.2mA    -32.31mA   -87.22mA
-540mV    -50.22mA   -28.51mA   -74.66mA
0V        0A         -200fA     0A
240mV     18.04mA    9.599mA    29.42mA
480mV     30.68mA    16.02mA    50.95mA
780mV     39.48mA    19.99mA    67.57mA
1.14V     41.99mA    20.78mA    74.01mA
2.82V     44.93mA    22.28mA    79.57mA
3.6V      44.93mA    22.28mA    79.57mA
[Pullup]
|Voltage   I(typ)   I(min)   I(max)
-1.8V     37.48mA    19.76mA    56.76mA
-540mV    37.48mA    19.76mA    56.76mA
-480mV    37.48mA    19.76mA    53.06mA
-360mV    28.94mA    18.48mA    39.74mA
0V        630fA      250pA      0A
300mV     -18.63mA   -11.6mA    -27.18mA
600mV     -31.41mA   -19.24mA   -46.67mA
780mV     -36.41mA   -22mA      -54.88mA
960mV     -39.54mA   -23.52mA   -60.64mA
1.2V      -41.44mA   -24.28mA   -64.94mA
1.56V     -42.42mA   -24.69mA   -67.24mA
3.6V      -44.2mA    -26mA      -70.5mA
[GND_clamp]
|Voltage   I(typ)   I(min)   I(max)
-1.8V     -9.908A    -9.683A    -9.994A
-1.2V     -3.383A    -4.084A    -2.934A
-1.16V    -2.841A    -3.655A    -2.294A
-1.12V    -2.299A    -3.226A    -1.656A
-1.04V    -1.218A    -2.369A    -414.2mA
-1V       -684.7mA   -1.941A    -119.2mA
-960mV    -257.2mA   -1.514A    -45.66mA
-920mV    -87.03mA   -1.089A    -28.93mA
-840mV    -19.35mA   -312.8mA   -18.97mA
-800mV    -13.55mA   -132.4mA   -15.49mA
-720mV    -8.042mA   -25.67mA   -9.491mA
1.8V      0A         13.64nA    0A
[POWER_clamp]
|Voltage   I(typ)   I(min)   I(max)
-1.8V     470.8mA    433.7mA    554.6mA
-1.14V    95.25mA    122.7mA    82.82mA
-1.12V    84.97mA    114mA      70.27mA
-1.06V    55.51mA    88.42mA    35.67mA
-1.04V    46.34mA    80.15mA    25.76mA
-1V       29.51mA    64.13mA    10.3mA
-940mV    10.39mA    41.86mA    1.109mA
-900mV    3.624mA    28.77mA    182.8uA
-840mV    490.7uA    13.24mA    11.35uA
-800mV    116.8uA    6.532mA    1.77uA
-740mV    13.2uA     1.724mA    109.3nA
0V        0A         18.75nA    0A
[Ramp]
| variable   typ   min   max
dV/dt_r  0.79770/33.88852n   0.58760/74.64501n   0.97668/17.96944n
dV/dt_f  0.83164/23.35009n   0.56497/59.10901n   1.02769/12.16381n
R_load = 50.000000
[Rising Waveform]
R_fixture= 50.000000
V_fixture= 1.800000
V_fixture_min= 1.600000
V_fixture_max= 2.000000
|time   V(typ)   V(min)   V(max)
0s        413.9mV    656.9mV    287.2mV
2.482ns   413.6mV    656.9mV    372.4mV
2.723ns   412.7mV    656.9mV    660.7mV
3.083ns   416.2mV    656.9mV    1.815V
3.483ns   470.7mV    656.9mV    1.978V
3.924ns   738.6mV    656.7mV    1.994V
4.404ns   1.614V     655.7mV    1.997V
4.885ns   1.778V     654.4mV    1.998V
7.728ns   1.799V     1.578V     2V
19.94ns   1.8V       1.6V       2V
[Rising Waveform]
R_fixture= 50.000000
V_fixture= 0.0
V_fixture_min= 0.0
V_fixture_max= 0.0
|time   V(typ)   V(min)   V(max)
0s        1.85nV     146.6nV    1.205nV
13.61ns   -220uV     -199.8uV   52.94mV
27.23ns   90.92mV    1.548mV    716.2mV
39.24ns   350.4mV    20.3mV     1.336V
58.46ns   837.6mV    122mV      1.565V
72.87ns   1.107V     244.2mV    1.602V
92.89ns   1.243V     428.1mV    1.62V
134.5ns   1.311V     744.4mV    1.627V
169ns     1.325V     878.2mV    1.628V
398.8ns   1.33V      980.3mV    1.628V
[Falling Waveform]
R_fixture= 50.000000
V_fixture= 1.800000
V_fixture_min= 1.600000
V_fixture_max= 2.000000
|time   V(typ)   V(min)   V(max)
0s        1.8V       1.6V       2V
16.82ns   1.8V       1.6V       1.929V
21.62ns   1.797V     1.6V       1.684V
35.24ns   1.624V     1.597V     575.1mV
54.45ns   934.1mV    1.535V     344.9mV
63.26ns   674.2mV    1.475V     322.4mV
78.48ns   534.1mV    1.33V      303.6mV
112.9ns   450.3mV    944.8mV    290.5mV
149.7ns   426.1mV    776.8mV    287.9mV
398.8ns   413.9mV    656.9mV    287.2mV
[Falling Waveform]
R_fixture= 50.000000
V_fixture= 0.0
V_fixture_min= 0.0
V_fixture_max= 0.0
|time   V(typ)   V(min)   V(max)
0s        1.33V      980.3mV    1.628V
1.842ns   1.331V     980.3mV    1.538V
2.162ns   1.334V     980.3mV    1.34V
2.723ns   1.198V     980.2mV    721.4mV
3.363ns   811.5mV    988.1mV    199.5mV
3.924ns   429.1mV    908mV      26.93mV
5.125ns   36.72mV    495.9mV    2.415mV
6.206ns   3.63mV     205.9mV    786.6uV
7.728ns   931.6uV    22.33mV    308.9uV
19.94ns   1.85nV     146.6nV    1.205nV
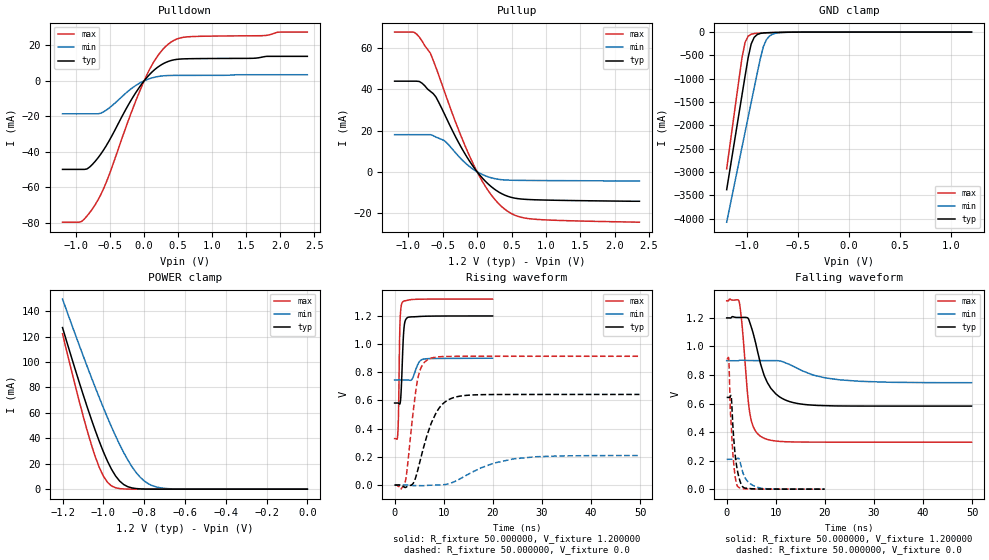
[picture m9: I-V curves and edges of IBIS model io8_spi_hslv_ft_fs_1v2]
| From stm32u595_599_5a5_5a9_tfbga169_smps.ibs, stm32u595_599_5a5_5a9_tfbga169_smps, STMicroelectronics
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|   Model io8_spi_hslv_ft_fs_1v2
[Model]  io8_spi_hslv_ft_fs_1v2
Model_type I/O
Polarity   Non-Inverting
Enable   Active-Low
Vinl =   0.360000V
Vinh =   0.840000V
Vmeas =  0.600000V
Cref =   50.000000pF
Rref =   100.000000M
Vref =   0.0V
C_comp   3.133100pF   3.070300pF   3.178200pF
[Temperature Range]   25.000000   0.140000k   -40.000000
[Pullup Reference]   1.200000V   0.900000V   1.320000V
[Pulldown Reference]   0.0V   0.0V   0.0V
[POWER Clamp Reference]   1.200000V   0.900000V   1.320000V
[GND Clamp Reference]   0.0V   0.0V   0.0V
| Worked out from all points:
|   slope of the pulldown table from 0 to 0.18 V, typ, clamps not added: 25.4 ohm
|   slope of the pullup table from 0 to 0.18 V, typ, clamps not added: 27.8 ohm
|   GND clamp passes 1 mA (typ) near -0.51 V on its own axis
|   POWER clamp passes 1 mA (typ) near -0.86 V on its own axis
|   rising waveform, R_fixture 50.000000, V_fixture 1.200000: 20-80 % time 444ps typ, 1.04ns min, 266ps max; typ from 0.582 V to 1.2 V
|   rising waveform, R_fixture 50.000000, V_fixture 0.0: 20-80 % time 3.59ns typ, 8.6ns min, 1.83ns max; typ from 0 V to 0.643 V
|   falling waveform, R_fixture 50.000000, V_fixture 1.200000: 20-80 % time 3.5ns typ, 7.67ns min, 1.53ns max; typ from 1.2 V to 0.582 V
|   falling waveform, R_fixture 50.000000, V_fixture 0.0: 20-80 % time 1.04ns typ, 1.77ns min, 824ps max; typ from 0.643 V to 0 V
[Pulldown]
|Voltage   I(typ)   I(min)   I(max)
-1.2V     -49.85mA   -18.57mA   -79.56mA
-920mV    -49.85mA   -18.57mA   -79.19mA
-840mV    -49.59mA   -18.57mA   -76.08mA
-720mV    -45.32mA   -18.57mA   -69.74mA
-560mV    -36.71mA   -16.58mA   -57.44mA
-200mV    -11.43mA   -4.74mA    -19.03mA
0V        0A         -500fA     0A
160mV     6.476mA    2.075mA    11.78mA
360mV     10.99mA    2.989mA    20.81mA
480mV     12.07mA    3.053mA    23.52mA
640mV     12.43mA    3.074mA    24.76mA
2.4V      13.78mA    3.432mA    27.43mA
[Pullup]
|Voltage   I(typ)   I(min)   I(max)
-1.2V     44mA       18.04mA    67.84mA
-920mV    44mA       18.04mA    67.83mA
-840mV    43.85mA    18.04mA    65.37mA
-680mV    39.07mA    18.04mA    57.58mA
-600mV    36.37mA    16.87mA    50.73mA
-480mV    28.4mA     15.19mA    39.49mA
-280mV    14.84mA    7.943mA    21.22mA
-80mV     3.667mA    1.75mA     5.47mA
160mV     -5.889mA   -2.43mA    -9.115mA
400mV     -11.31mA   -3.958mA   -18.11mA
800mV     -13.54mA   -4.214mA   -22.92mA
2.36V     -14.3mA    -4.5mA     -24.47mA
[GND_clamp]
|Voltage   I(typ)   I(min)   I(max)
-1.2V     -3.379A    -4.076A    -2.932A
-1.05V    -1.35A     -2.47A     -550.7mA
-1.02V    -947.8mA   -2.149A    -221.5mA
-990mV    -552.4mA   -1.829A    -88.44mA
-960mV    -255.3mA   -1.51A     -44.87mA
-930mV    -111.8mA   -1.191A    -30.68mA
-870mV    -28.35mA   -564.6mA   -21.34mA
-840mV    -18.65mA   -309.5mA   -18.49mA
-810mV    -14.07mA   -161.6mA   -15.92mA
-780mV    -11.37mA   -83.33mA   -13.53mA
-600mV    -3.009mA   -4.321mA   -3.091mA
1.2V      0A         13.65nA    0A
[POWER_clamp]
|Voltage   I(typ)   I(min)   I(max)
-1.2V     127mA      149.4mA    122.2mA
-1.12V    84.97mA    114mA      70.27mA
-1.06V    55.51mA    88.42mA    35.67mA
-1.02V    37.63mA    72.04mA    17.17mA
-1V       29.51mA    64.13mA    10.3mA
-960mV    15.69mA    48.99mA    2.571mA
-900mV    3.624mA    28.77mA    182.8uA
-840mV    490.7uA    13.24mA    11.35uA
-800mV    116.8uA    6.532mA    1.77uA
-740mV    13.2uA     1.723mA    109.1nA
-620mV    167.4nA    79.36uA    0A
0V        0A         17.87nA    0A
[Ramp]
| variable   typ   min   max
dV/dt_r  0.38561/3.58494n   0.12546/8.59424n   0.54824/1.82578n
dV/dt_f  0.37078/3.49963n   92.37000m/7.68214n  0.59435/1.52863n
R_load = 50.000000
[Rising Waveform]
R_fixture= 50.000000
V_fixture= 1.200000
V_fixture_min= 0.900000
V_fixture_max= 1.320000
|time   V(typ)   V(min)   V(max)
0s        582mV      746mV      329.5mV
680.7ps   582mV      746mV      382.4mV
800.8ps   580.5mV    746mV      513.3mV
1.001ns   574.5mV    746mV      1.003V
1.121ns   579.9mV    746mV      1.174V
1.602ns   902.3mV    746mV      1.298V
1.962ns   1.13V      746.1mV    1.306V
2.683ns   1.19V      745.3mV    1.312V
5.846ns   1.198V     893.3mV    1.319V
19.94ns   1.2V       900mV      1.32V
[Rising Waveform]
R_fixture= 50.000000
V_fixture= 0.0
V_fixture_min= 0.0
V_fixture_max= 0.0
|time   V(typ)   V(min)   V(max)
0s        -1.826uV   1.348uV    -19.27uV
2.102ns   -17.17mV   5.503uV    13.65mV
3.704ns   8.276mV    -3.9mV     495.1mV
4.605ns   91.32mV    -3.842mV   732.6mV
5.405ns   200.8mV    -4.756mV   834.2mV
6.607ns   353.1mV    -2.765mV   887mV
9.109ns   548.5mV    59.28uV    910.5mV
13.01ns   629mV      38.19mV    913.7mV
24.22ns   642.7mV    185.5mV    913.9mV
49.85ns   642.8mV    209.3mV    913.9mV
[Falling Waveform]
R_fixture= 50.000000
V_fixture= 1.200000
V_fixture_min= 0.900000
V_fixture_max= 1.320000
|time   V(typ)   V(min)   V(max)
0s        1.2V       900mV      1.32V
2.503ns   1.203V     901.4mV    1.318V
3.103ns   1.204V     903.7mV    1.159V
4.705ns   1.168V     901.3mV    533.8mV
5.606ns   1.064V     901.1mV    423.5mV
7.207ns   843.4mV    901mV      363.9mV
10.01ns   667.3mV    900.7mV    337.4mV
14.71ns   598.6mV    841.2mV    330.3mV
22.92ns   583mV      766.4mV    329.5mV
49.85ns   582mV      746mV      329.5mV
[Falling Waveform]
R_fixture= 50.000000
V_fixture= 0.0
V_fixture_min= 0.0
V_fixture_max= 0.0
|time   V(typ)   V(min)   V(max)
0s        642.8mV    209.3mV    913.9mV
440.4ps   642.7mV    209.3mV    899.6mV
720.7ps   648.7mV    209.4mV    581.1mV
920.9ps   650.1mV    209.4mV    448.9mV
1.201ns   481mV      209.4mV    278.4mV
1.522ns   318.3mV    209.2mV    148.4mV
2.242ns   120.6mV    216.2mV    19.04mV
3.323ns   14.61mV    113.3mV    3.34mV
5.966ns   1.761mV    16.71mV    446.1uV
19.94ns   -1.826uV   1.348uV    -19.27uV
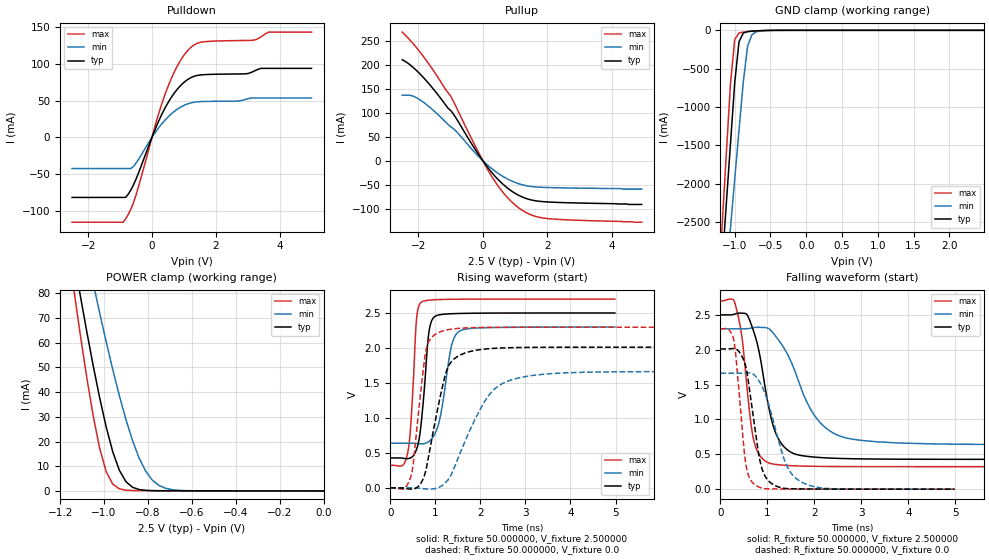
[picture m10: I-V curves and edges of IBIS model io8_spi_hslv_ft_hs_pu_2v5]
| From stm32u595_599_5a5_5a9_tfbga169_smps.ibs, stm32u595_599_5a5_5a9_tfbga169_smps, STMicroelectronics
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|   Model io8_spi_hslv_ft_hs_pu_2v5
[Model]  io8_spi_hslv_ft_hs_pu_2v5
Model_type I/O
Polarity   Non-Inverting
Enable   Active-Low
Vinl =   0.750000V
Vinh =   1.750000V
Vmeas =  1.250000V
Cref =   50.000000pF
Rref =   100.000000M
Vref =   0.0V
C_comp   3.438200pF   3.436700pF   3.473300pF
[Temperature Range]   25.000000   0.140000k   -40.000000
[Pullup Reference]   2.500000V   2.300000V   2.700000V
[Pulldown Reference]   0.0V   0.0V   0.0V
[POWER Clamp Reference]   2.500000V   2.300000V   2.700000V
[GND Clamp Reference]   0.0V   0.0V   0.0V
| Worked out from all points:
|   slope of the pulldown table from 0 to 0.375 V, typ, clamps not added: 10.1 ohm
|   slope of the pullup table from 0 to 0.375 V, typ, clamps not added: 11.7 ohm
|   GND clamp passes 1 mA (typ) near -0.50 V on its own axis
|   POWER clamp passes 1 mA (typ) near -0.85 V on its own axis
|   rising waveform, R_fixture 50.000000, V_fixture 2.500000: 20-80 % time 161ps typ, 245ps min, 119ps max; typ from 0.428 V to 2.5 V
|   rising waveform, R_fixture 50.000000, V_fixture 0.0: 20-80 % time 383ps typ, 749ps min, 231ps max; typ from 0 V to 2.01 V
|   falling waveform, R_fixture 50.000000, V_fixture 2.500000: 20-80 % time 372ps typ, 702ps min, 233ps max; typ from 2.5 V to 0.428 V
|   falling waveform, R_fixture 50.000000, V_fixture 0.0: 20-80 % time 263ps typ, 442ps min, 182ps max; typ from 2.01 V to 0 V
[Pulldown]
|Voltage   I(typ)   I(min)   I(max)
-2.5V     -81.61mA   -42.31mA   -115.3mA
-900mV    -81.61mA   -42.31mA   -115.3mA
-820mV    -81.42mA   -42.31mA   -110.6mA
-500mV    -56.95mA   -35.08mA   -78.57mA
140mV     15.18mA    9.02mA     22.02mA
460mV     44mA       25.98mA    64.37mA
860mV     68.91mA    40.27mA    102.2mA
1.26V     82.21mA    47.42mA    124mA
1.66V     85.53mA    48.99mA    130.3mA
3.18V     89.84mA    53.63mA    132.3mA
3.66V     94mA       53.63mA    143.4mA
5V        94mA       53.63mA    143.4mA
[Pullup]
|Voltage   I(typ)   I(min)   I(max)
-2.5V     210.9mA    137mA      268.6mA
-2.2V     197.1mA    135.8mA    247.3mA
-1.96V    182mA      127.7mA    227.8mA
-1V       105.1mA    71.23mA    135.1mA
-840mV    89.99mA    62.53mA    114.1mA
-200mV    19.92mA    13.68mA    26.11mA
200mV     -18.15mA   -12.19mA   -24.3mA
600mV     -47.45mA   -31.77mA   -63.92mA
1.08V     -70.88mA   -47.09mA   -96.6mA
1.48V     -81.29mA   -53.4mA    -112.4mA
1.96V     -85.56mA   -55.61mA   -120.1mA
4.92V     -91mA      -59mA      -128mA
[GND_clamp]
|Voltage   I(typ)   I(min)   I(max)
-2.5V     -9.641A    -9.693A    -9.352A
-1.18V    -3.114A    -3.874A    -2.614A
-1.12V    -2.301A    -3.23A     -1.656A
-1.06V    -1.489A    -2.587A    -706.2mA
-1V       -685.8mA   -1.945A    -119.3mA
-940mV    -149.7mA   -1.304A    -34.73mA
-880mV    -35.54mA   -672.6mA   -23.06mA
-820mV    -16.19mA   -206.4mA   -17.27mA
-760mV    -10.58mA   -57.55mA   -12.41mA
-700mV    -7.152mA   -18.74mA   -8.24mA
-400mV    -103.3uA   -378.5uA   -41.74uA
2.48V     0A         13.22nA    0A
[POWER_clamp]
|Voltage   I(typ)   I(min)   I(max)
-2.49V    881.1mA    773.1mA    1.07A
-1.14V    95.32mA    122.8mA    82.93mA
-1.11V    79.97mA    109.7mA    64.26mA
-1.05V    50.95mA    84.3mA     30.69mA
-1.02V    37.7mA     72.08mA    17.29mA
-990mV    25.79mA    60.29mA    7.738mA
-930mV    8.312mA    38.47mA    853.1uA
-900mV    3.712mA    28.81mA    313.6uA
-840mV    566.2uA    13.29mA    123.7uA
-780mV    119.1uA    4.365mA    94.04uA
-660mV    38.99uA    251.5uA    57.77uA
0V        0A         18.93nA    0A
[Ramp]
| variable   typ   min   max
dV/dt_r  1.20644/0.38252n   0.99759/0.74788n   1.37763/0.23027n
dV/dt_f  1.24312/0.37116n   0.99702/0.70142n   1.42607/0.23224n
R_load = 50.000000
[Rising Waveform]
R_fixture= 50.000000
V_fixture= 2.500000
V_fixture_min= 2.300000
V_fixture_max= 2.700000
|time   V(typ)   V(min)   V(max)
0s        428.2mV    638.2mV    323.3mV
390.4ps   418.7mV    638.3mV    513.3mV
460.5ps   432.8mV    638.3mV    957.9mV
580.6ps   547.6mV    635.4mV    2.394V
690.7ps   950.6mV    630.5mV    2.656V
850.9ps   2.192V     660.4mV    2.683V
1.011ns   2.457V     800.2mV    2.69V
1.361ns   2.49V      2.036V     2.696V
1.552ns   2.493V     2.246V     2.697V
4.985ns   2.5V       2.3V       2.699V
[Rising Waveform]
R_fixture= 50.000000
V_fixture= 0.0
V_fixture_min= 0.0
V_fixture_max= 0.0
|time   V(typ)   V(min)   V(max)
0s        453.7uV    545.8uV    473.7uV
440.4ps   -16.74mV   691.2uV    129.5mV
500.5ps   -17.58mV   624.4uV    299.4mV
800.8ps   284.6mV    -15.24mV   1.994V
1.121ns   1.34V      22.07mV    2.234V
1.281ns   1.726V     114.1mV    2.261V
1.481ns   1.874V     387.7mV    2.278V
2.142ns   1.987V     1.283V     2.294V
2.703ns   2.005V     1.547V     2.296V
9.97ns    2.011V     1.663V     2.296V
[Falling Waveform]
R_fixture= 50.000000
V_fixture= 2.500000
V_fixture_min= 2.300000
V_fixture_max= 2.700000
|time   V(typ)   V(min)   V(max)
0s        2.5V       2.3V       2.699V
320.3ps   2.515V     2.3V       2.641V
460.5ps   2.524V     2.299V     2.171V
580.6ps   2.487V     2.303V     1.36V
740.7ps   2.194V     2.32V      624.1mV
1.041ns   1.138V     2.298V     373.8mV
1.461ns   546.5mV    1.89V      338.8mV
2.022ns   459.2mV    1.039V     327.8mV
2.683ns   438.7mV    734.1mV    324.5mV
9.97ns    428.2mV    638.2mV    323.3mV
[Falling Waveform]
R_fixture= 50.000000
V_fixture= 0.0
V_fixture_min= 0.0
V_fixture_max= 0.0
|time   V(typ)   V(min)   V(max)
0s        2.011V     1.663V     2.296V
280.3ps   2.018V     1.663V     2.154V
540.5ps   1.759V     1.667V     364.2mV
620.6ps   1.422V     1.668V     160mV
760.8ps   749.1mV    1.61V      52.09mV
870.9ps   327.6mV    1.494V     18.66mV
1.021ns   122mV      1.232V     5.954mV
1.381ns   10.96mV    383.6mV    2.753mV
1.702ns   4.202mV    112mV      1.61mV
4.985ns   453.7uV    545.8uV    473.7uV
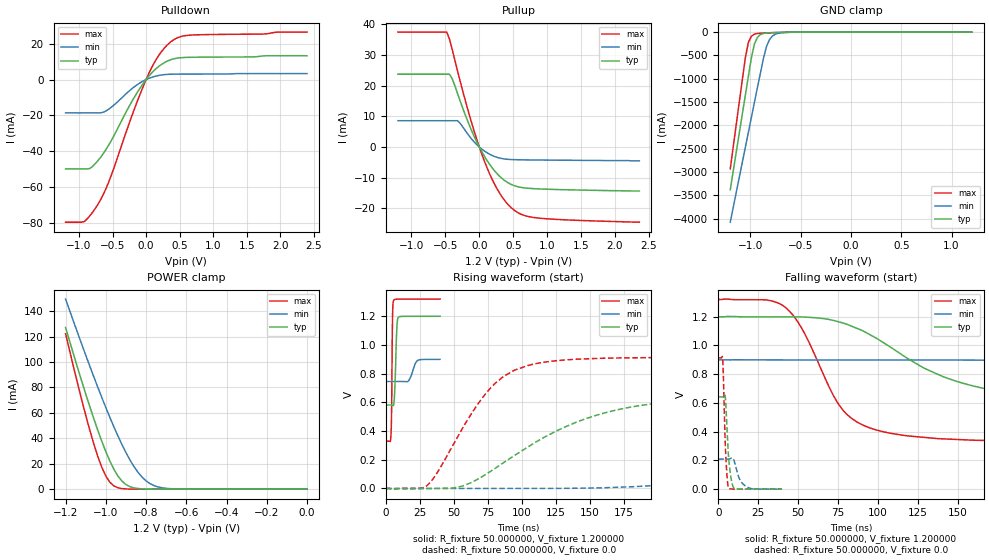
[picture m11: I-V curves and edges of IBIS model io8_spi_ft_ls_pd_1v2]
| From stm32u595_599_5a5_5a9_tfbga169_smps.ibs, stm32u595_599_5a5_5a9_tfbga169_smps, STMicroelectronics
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|   Model io8_spi_ft_ls_pd_1v2
[Model]  io8_spi_ft_ls_pd_1v2
Model_type I/O
Polarity   Non-Inverting
Enable   Active-Low
Vinl =   0.360000V
Vinh =   0.840000V
Vmeas =  0.600000V
Cref =   50.000000pF
Rref =   100.000000M
Vref =   0.0V
C_comp   3.132800pF   3.069700pF   3.178000pF
[Temperature Range]   25.000000   0.140000k   -40.000000
[Pullup Reference]   1.200000V   0.900000V   1.320000V
[Pulldown Reference]   0.0V   0.0V   0.0V
[POWER Clamp Reference]   1.200000V   0.900000V   1.320000V
[GND Clamp Reference]   0.0V   0.0V   0.0V
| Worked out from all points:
|   slope of the pulldown table from 0 to 0.18 V, typ, clamps not added: 25.4 ohm
|   slope of the pullup table from 0 to 0.18 V, typ, clamps not added: 27.8 ohm
|   GND clamp passes 1 mA (typ) near -0.51 V on its own axis
|   POWER clamp passes 1 mA (typ) near -0.86 V on its own axis
|   rising waveform, R_fixture 50.000000, V_fixture 1.200000: 20-80 % time 1.25ns typ, 3.35ns min, 597ps max; typ from 0.581 V to 1.2 V
|   rising waveform, R_fixture 50.000000, V_fixture 0.0: 20-80 % time 77.8ns typ, 193ns min, 37.8ns max; typ from 0 V to 0.642 V
|   falling waveform, R_fixture 50.000000, V_fixture 1.200000: 20-80 % time 69.8ns typ, 186ns min, 27.7ns max; typ from 1.2 V to 0.581 V
|   falling waveform, R_fixture 50.000000, V_fixture 0.0: 20-80 % time 2.24ns typ, 4.29ns min, 1.61ns max; typ from 0.642 V to 0 V
[Pulldown]
|Voltage   I(typ)   I(min)   I(max)
-1.2V     -49.85mA   -18.57mA   -79.56mA
-920mV    -49.85mA   -18.57mA   -79.19mA
-840mV    -49.59mA   -18.57mA   -76.08mA
-720mV    -45.32mA   -18.57mA   -69.74mA
-560mV    -36.71mA   -16.58mA   -57.44mA
-200mV    -11.43mA   -4.739mA   -19.03mA
0V        -10fA      -600fA     0A
160mV     6.476mA    2.074mA    11.78mA
360mV     10.99mA    2.988mA    20.81mA
480mV     12.07mA    3.052mA    23.52mA
640mV     12.42mA    3.073mA    24.76mA
2.4V      13.31mA    3.339mA    26.51mA
[Pullup]
|Voltage   I(typ)   I(min)   I(max)
-1.2V     23.7mA     8.568mA    37.41mA
-480mV    23.7mA     8.568mA    37.41mA
-440mV    23.7mA     8.568mA    35.14mA
-400mV    22.24mA    8.568mA    31.81mA
-320mV    17.36mA    8.568mA    24.69mA
-120mV    5.681mA    2.787mA    8.394mA
80mV      -3.179mA   -1.366mA   -4.88mA
280mV     -9.096mA   -3.48mA    -14.29mA
520mV     -12.61mA   -4.111mA   -20.65mA
680mV     -13.33mA   -4.182mA   -22.38mA
920mV     -13.66mA   -4.239mA   -23.22mA
2.36V     -14.3mA    -4.5mA     -24.46mA
[GND_clamp]
|Voltage   I(typ)   I(min)   I(max)
-1.2V     -3.379A    -4.076A    -2.932A
-1.05V    -1.35A     -2.47A     -550.7mA
-1.02V    -947.8mA   -2.15A     -221.5mA
-990mV    -552.4mA   -1.829A    -88.45mA
-960mV    -255.3mA   -1.51A     -44.89mA
-930mV    -111.8mA   -1.191A    -30.69mA
-870mV    -28.36mA   -564.6mA   -21.36mA
-840mV    -18.66mA   -309.5mA   -18.51mA
-810mV    -14.08mA   -161.6mA   -15.94mA
-780mV    -11.38mA   -83.33mA   -13.55mA
-600mV    -3.019mA   -4.329mA   -3.104mA
1.2V      30.28uA    18.17uA    37.27uA
[POWER_clamp]
|Voltage   I(typ)   I(min)   I(max)
-1.2V     127mA      149.4mA    122.2mA
-1.12V    84.97mA    114mA      70.27mA
-1.06V    55.51mA    88.42mA    35.67mA
-1.02V    37.63mA    72.04mA    17.17mA
-1V       29.51mA    64.13mA    10.3mA
-960mV    15.69mA    48.99mA    2.571mA
-900mV    3.624mA    28.77mA    182.8uA
-840mV    490.7uA    13.24mA    11.35uA
-800mV    116.8uA    6.532mA    1.77uA
-740mV    13.2uA     1.724mA    109.1nA
-620mV    167.4nA    79.36uA    0A
0V        0A         17.87nA    0A
[Ramp]
| variable   typ   min   max
dV/dt_r  0.38525/77.76357n   0.12524/0.19254u   0.54787/37.79509n
dV/dt_f  0.37090/69.74405n   92.37000m/0.18599u  0.59416/27.69438n
R_load = 50.000000
[Rising Waveform]
R_fixture= 50.000000
V_fixture= 1.200000
V_fixture_min= 0.900000
V_fixture_max= 1.320000
|time   V(typ)   V(min)   V(max)
0s        581.3mV    745.2mV    329.2mV
3.764ns   581.5mV    745.2mV    371.4mV
4.244ns   581.3mV    745.2mV    556.4mV
4.885ns   579.2mV    745.2mV    1.177V
5.606ns   578.5mV    745.2mV    1.307V
6.647ns   706.5mV    745.2mV    1.317V
8.088ns   1.119V     745.2mV    1.319V
8.969ns   1.19V      745.2mV    1.319V
23.06ns   1.2V       890.6mV    1.319V
39.88ns   1.2V       899.5mV    1.319V
[Rising Waveform]
R_fixture= 50.000000
V_fixture= 0.0
V_fixture_min= 0.0
V_fixture_max= 0.0
|time   V(typ)   V(min)   V(max)
0s        1.941nV    235.2nV    1.147nV
30.03ns   -131.6uV   -196.2uV   17.8mV
56.06ns   15.68mV    -31.44uV   413.2mV
80.08ns   138mV      9.382uV    729.6mV
96.1ns    238.5mV    115.8uV    828.8mV
126.1ns   403.3mV    572.4uV    890.5mV
174.2ns   555.8mV    9.601mV    909.3mV
244.2ns   624.8mV    55.51mV    912.9mV
466.5ns   642mV      182.5mV    913.1mV
997ns     642.1mV    209mV      913.1mV
[Falling Waveform]
R_fixture= 50.000000
V_fixture= 1.200000
V_fixture_min= 0.900000
V_fixture_max= 1.320000
|time   V(typ)   V(min)   V(max)
0s        1.2V       899.5mV    1.319V
40.04ns   1.198V     899.1mV    1.28V
52.05ns   1.198V     899.1mV    1.122V
72.07ns   1.174V     899.1mV    650mV
82.08ns   1.139V     899.1mV    504mV
136.1ns   804.5mV    898.7mV    352.5mV
194.2ns   651.5mV    894.3mV    333.3mV
298.3ns   591.7mV    841.9mV    329.4mV
478.5ns   581.3mV    767.8mV    329.2mV
997ns     581.3mV    745.2mV    329.2mV
[Falling Waveform]
R_fixture= 50.000000
V_fixture= 0.0
V_fixture_min= 0.0
V_fixture_max= 0.0
|time   V(typ)   V(min)   V(max)
0s        642.1mV    209mV      913.1mV
2.803ns   641.8mV    209.1mV    904.5mV
4.645ns   611.8mV    209mV      257.1mV
5.606ns   403mV      208.8mV    78.2mV
6.486ns   225.5mV    209mV      8.857mV
8.168ns   66.39mV    215.8mV    1.464mV
10.17ns   2.717mV    189.7mV    258.8uV
13.53ns   572.9uV    66.24mV    -48.63uV
18.26ns   37.74uV    12.83mV    -64.08uV
39.88ns   1.941nV    235.2nV    1.147nV
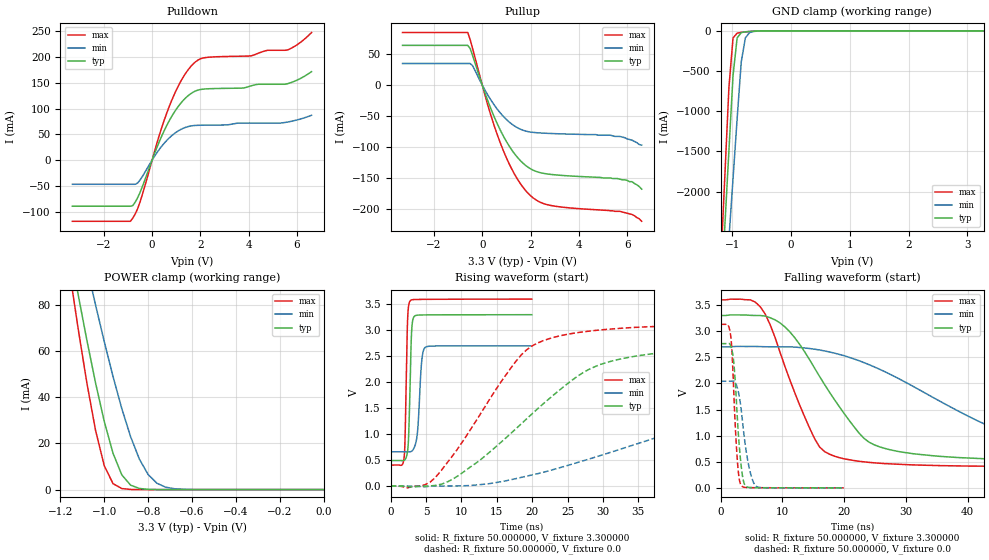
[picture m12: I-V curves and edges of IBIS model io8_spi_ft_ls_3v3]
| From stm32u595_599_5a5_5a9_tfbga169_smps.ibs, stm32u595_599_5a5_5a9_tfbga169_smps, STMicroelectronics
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|   Model io8_spi_ft_ls_3v3
[Model]  io8_spi_ft_ls_3v3
Model_type I/O
Polarity   Non-Inverting
Enable   Active-Low
Vinl =   0.990000V
Vinh =   2.310000V
Vmeas =  1.650000V
Cref =   50.000000pF
Rref =   100.000000M
Vref =   0.0V
C_comp   3.495300pF   3.468500pF   3.534700pF
[Temperature Range]   25.000000   0.140000k   -40.000000
[Pullup Reference]   3.300000V   2.700000V   3.600000V
[Pulldown Reference]   0.0V   0.0V   0.0V
[POWER Clamp Reference]   3.300000V   2.700000V   3.600000V
[GND Clamp Reference]   0.0V   0.0V   0.0V
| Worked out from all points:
|   slope of the pulldown table from 0 to 0.495 V, typ, clamps not added: 8.73 ohm
|   slope of the pullup table from 0 to 0.495 V, typ, clamps not added: 9.64 ohm
|   GND clamp passes 1 mA (typ) near -0.50 V on its own axis
|   POWER clamp passes 1 mA (typ) near -0.85 V on its own axis
|   rising waveform, R_fixture 50.000000, V_fixture 3.300000: 20-80 % time 328ps typ, 507ps min, 284ps max; typ from 0.49 V to 3.3 V
|   rising waveform, R_fixture 50.000000, V_fixture 0.0: 20-80 % time 14.4ns typ, 31.2ns min, 9.33ns max; typ from 0 V to 2.76 V
|   falling waveform, R_fixture 50.000000, V_fixture 3.300000: 20-80 % time 9.54ns typ, 21.1ns min, 6.27ns max; typ from 3.3 V to 0.49 V
|   falling waveform, R_fixture 50.000000, V_fixture 0.0: 20-80 % time 950ps typ, 1.4ns min, 772ps max; typ from 2.76 V to 0 V
[Pulldown]
|Voltage   I(typ)   I(min)   I(max)
-3.3V     -89.71mA   -47.06mA   -119mA
-900mV    -89.71mA   -47.06mA   -119mA
-700mV    -81.75mA   -47.06mA   -104.8mA
-500mV    -62.92mA   -38.71mA   -81.44mA
300mV     36.2mA     21.01mA    48.7mA
800mV     84.06mA    46.96mA    114.8mA
1.3V      116.7mA    62.08mA    162.3mA
1.8V      134.4mA    67.38mA    191.2mA
2.2V      138.3mA    67.91mA    199.2mA
4.1V      144.4mA    71.97mA    202.7mA
5.6V      148.4mA    73.95mA    213.9mA
6.6V      171.9mA    87.1mA     247.9mA
[Pullup]
|Voltage   I(typ)   I(min)   I(max)
-3.3V     64.06mA    34.74mA    84.71mA
-600mV    64.06mA    34.74mA    84.71mA
-400mV    47.78mA    31.25mA    59.06mA
300mV     -32.62mA   -20.62mA   -41.63mA
800mV     -76.87mA   -47.45mA   -98.74mA
1.4V      -114.1mA   -67.68mA   -148.3mA
1.7V      -126.6mA   -73.14mA   -165.8mA
2.1V      -137.3mA   -76.42mA   -182mA
3V        -144.9mA   -78.48mA   -195.5mA
5.9V      -153mA     -85mA      -206mA
6.2V      -156mA     -89mA      -209mA
6.6V      -168mA     -97mA      -220mA
[GND_clamp]
|Voltage   I(typ)   I(min)   I(max)
-3.3V     -9.098A    -9.372A    -9.671A
-1.2V     -3.386A    -4.091A    -2.933A
-1.13V    -2.437A    -3.34A     -1.815A
-1.06V    -1.49A     -2.588A    -705.6mA
-990mV    -555.7mA   -1.839A    -89.03mA
-920mV    -88.12mA   -1.093A    -28.78mA
-850mV    -22.35mA   -387.4mA   -19.84mA
-780mV    -12.12mA   -88mA      -13.87mA
-710mV    -7.709mA   -22.52mA   -8.846mA
-640mV    -4.545mA   -7.864mA   -4.87mA
-360mV    -31.12uA   -173.5uA   -8.496uA
3.28V     0A         14.15nA    -7.901nA
[POWER_clamp]
|Voltage   I(typ)   I(min)   I(max)
-3.28V    1.355A     1.167A     1.664A
-1.16V    105.7mA    131.6mA    95.69mA
-1.12V    84.97mA    114mA      70.27mA
-1.08V    65.05mA    96.83mA    46.54mA
-1.04V    46.34mA    80.15mA    25.76mA
-1V       29.51mA    64.13mA    10.3mA
-960mV    15.69mA    48.99mA    2.571mA
-920mV    6.373mA    35.1mA     455.6uA
-840mV    490.7uA    13.24mA    11.36uA
-760mV    27.33uA    2.767mA    279.2nA
-640mV    348nA      134.1uA    17.42nA
0V        0A         19.95nA    0A
[Ramp]
| variable   typ   min   max
dV/dt_r  1.65714/14.37876n   1.22460/31.19417n   1.87860/9.31534n
dV/dt_f  1.68606/9.53013n   1.22413/21.03367n   1.91789/6.24144n
R_load = 50.000000
[Rising Waveform]
R_fixture= 50.000000
V_fixture= 3.300000
V_fixture_min= 2.700000
V_fixture_max= 3.600000
|time   V(typ)   V(min)   V(max)
0s        489.9mV    659.8mV    403.5mV
1.922ns   492.8mV    659.8mV    559.9mV
2.042ns   507.4mV    659.8mV    899.6mV
2.402ns   672.5mV    659.3mV    3.197V
2.763ns   1.963V     659.7mV    3.566V
3.123ns   3.187V     689.4mV    3.589V
3.764ns   3.291V     990.1mV    3.594V
4.364ns   3.295V     2.354V     3.595V
4.845ns   3.296V     2.664V     3.595V
19.94ns   3.3V       2.7V       3.6V
[Rising Waveform]
R_fixture= 50.000000
V_fixture= 0.0
V_fixture_min= 0.0
V_fixture_max= 0.0
|time   V(typ)   V(min)   V(max)
0s        15.77nV    114.3nV    49.88nV
6.406ns   12.13mV    -749.1uV   176.8mV
12.01ns   435.7mV    18.99mV    1.241V
16.82ns   991.8mV    115.9mV    2.241V
20.02ns   1.394V     214mV      2.702V
27.23ns   2.187V     486mV      2.97V
34.43ns   2.498V     795.8mV    3.055V
57.66ns   2.712V     1.658V     3.121V
88.09ns   2.754V     1.941V     3.13V
398.8ns   2.762V     2.041V     3.131V
[Falling Waveform]
R_fixture= 50.000000
V_fixture= 3.300000
V_fixture_min= 2.700000
V_fixture_max= 3.600000
|time   V(typ)   V(min)   V(max)
0s        3.3V       2.7V       3.6V
6.406ns   3.3V       2.704V     3.468V
8.008ns   3.257V     2.701V     3.125V
11.21ns   2.985V     2.699V     2.064V
16.02ns   2.132V     2.64V      782.4mV
22.42ns   1.046V     2.433V     508.9mV
26.43ns   760.3mV    2.233V     465.5mV
46.45ns   543.1mV    1.066V     411.4mV
70.47ns   503.1mV    786mV      404.7mV
398.8ns   489.9mV    659.8mV    403.5mV
[Falling Waveform]
R_fixture= 50.000000
V_fixture= 0.0
V_fixture_min= 0.0
V_fixture_max= 0.0
|time   V(typ)   V(min)   V(max)
0s        2.762V     2.041V     3.131V
1.161ns   2.763V     2.041V     3.124V
1.642ns   2.712V     2.041V     2.889V
2.162ns   2.343V     2.042V     1.705V
2.683ns   1.364V     1.92V      548.1mV
3.003ns   811.9mV    1.752V     171.2mV
3.363ns   371.7mV    1.455V     41.35mV
4.404ns   11.93mV    506.5mV    5.207mV
5.686ns   2.849mV    36.4mV     3.186mV
19.94ns   15.77nV    114.3nV    49.88nV
